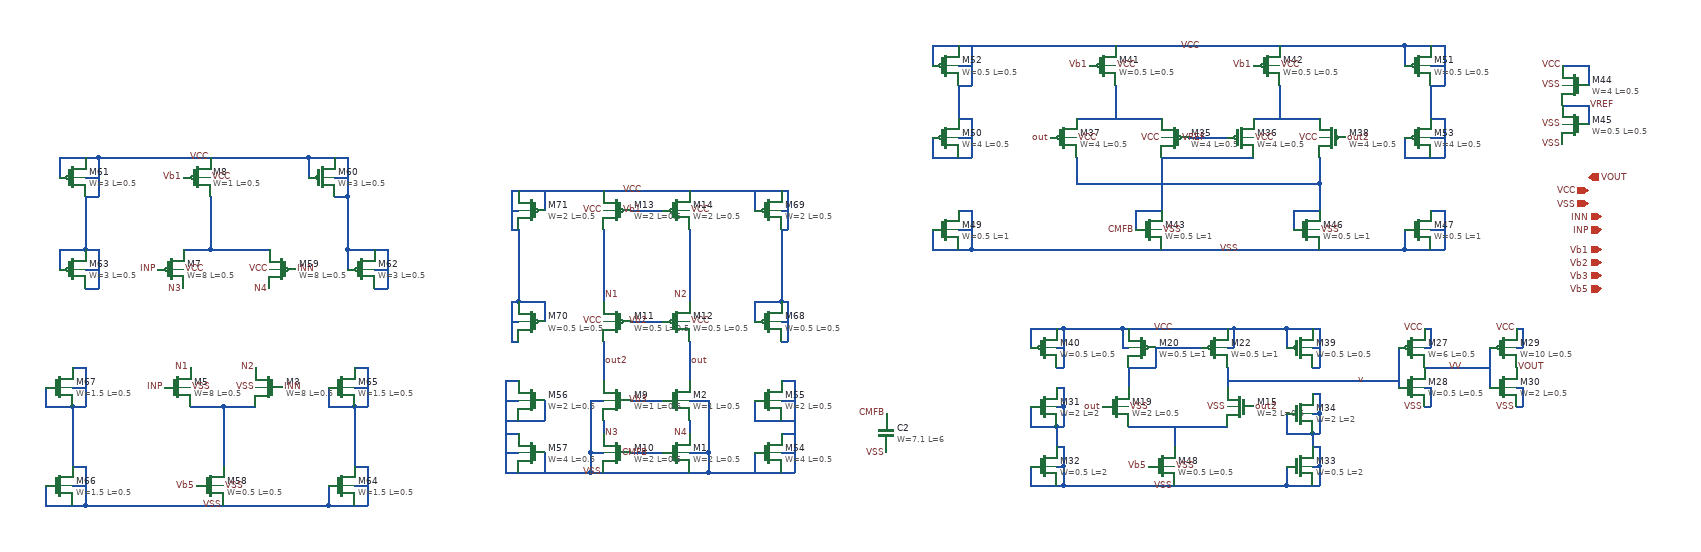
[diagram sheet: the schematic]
v {xschem version=3.4.0 file_version=1.2
}
G {}
K {}
V {}
S {}
E {}
N -1170 440 -1120 440 {
lab=#net1}
N -1190 200 -1100 200 {
lab=#net2}
N -1190 180 -1190 200 {
lab=#net2}
N -1220 440 -1170 440 {
lab=#net1}
N -1230 200 -1190 200 {
lab=#net2}
N -1170 440 -1170 470 {
lab=#net1}
N -1170 470 -1170 530 {
lab=#net1}
N -1190 120 -1190 180 {
lab=#net2}
N -1040 60 -1040 90 {
lab=VCC}
N -1040 60 -1000 60 {
lab=VCC}
N -1000 120 -990 120 {
lab=VCC}
N -990 120 -980 120 {
lab=VCC}
N -980 60 -980 120 {
lab=VCC}
N -1000 60 -980 60 {
lab=VCC}
N -1000 90 -980 90 {
lab=VCC}
N -1190 60 -1040 60 {
lab=VCC}
N -1420 60 -1420 90 {
lab=VCC}
N -1420 60 -1380 60 {
lab=VCC}
N -1380 120 -1370 120 {
lab=VCC}
N -1370 120 -1360 120 {
lab=VCC}
N -1360 60 -1360 120 {
lab=VCC}
N -1380 60 -1360 60 {
lab=VCC}
N -1380 90 -1360 90 {
lab=VCC}
N -1360 60 -1190 60 {
lab=VCC}
N -980 200 -980 230 {
lab=VCC}
N -980 200 -940 200 {
lab=VCC}
N -940 260 -930 260 {
lab=VCC}
N -930 260 -920 260 {
lab=VCC}
N -920 200 -920 260 {
lab=VCC}
N -940 200 -920 200 {
lab=VCC}
N -940 230 -920 230 {
lab=VCC}
N -980 120 -980 200 {
lab=VCC}
N -1420 200 -1420 230 {
lab=VCC}
N -1420 200 -1380 200 {
lab=VCC}
N -1380 260 -1370 260 {
lab=VCC}
N -1370 260 -1360 260 {
lab=VCC}
N -1360 200 -1360 260 {
lab=VCC}
N -1380 200 -1360 200 {
lab=VCC}
N -1380 230 -1360 230 {
lab=VCC}
N -1380 120 -1380 200 {
lab=VCC}
N -1010 590 -970 590 {
lab=VSS}
N -1010 560 -1010 590 {
lab=VSS}
N -970 530 -950 530 {
lab=VSS}
N -950 530 -950 590 {
lab=VSS}
N -970 590 -950 590 {
lab=VSS}
N -1170 590 -1010 590 {
lab=VSS}
N -970 560 -950 560 {
lab=VSS}
N -1010 440 -970 440 {
lab=VSS}
N -1010 410 -1010 440 {
lab=VSS}
N -970 380 -950 380 {
lab=VSS}
N -950 380 -950 440 {
lab=VSS}
N -970 440 -950 440 {
lab=VSS}
N -970 410 -950 410 {
lab=VSS}
N -970 440 -970 530 {
lab=VSS}
N -1440 590 -1400 590 {
lab=VSS}
N -1440 560 -1440 590 {
lab=VSS}
N -1400 530 -1380 530 {
lab=VSS}
N -1380 530 -1380 590 {
lab=VSS}
N -1400 590 -1380 590 {
lab=VSS}
N -1400 560 -1380 560 {
lab=VSS}
N -1440 440 -1400 440 {
lab=VSS}
N -1440 410 -1440 440 {
lab=VSS}
N -1400 380 -1380 380 {
lab=VSS}
N -1380 380 -1380 440 {
lab=VSS}
N -1400 440 -1380 440 {
lab=VSS}
N -1400 410 -1380 410 {
lab=VSS}
N -1400 440 -1400 530 {
lab=VSS}
N -1380 590 -1170 590 {
lab=VSS}
N -610 510 -590 510 {
lab=VSS}
N -610 510 -610 540 {
lab=VSS}
N -610 540 -430 540 {
lab=VSS}
N -430 510 -430 540 {
lab=VSS}
N -460 510 -430 510 {
lab=VSS}
N -460 460 -460 480 {
lab=N4}
N -590 460 -590 480 {
lab=N3}
N -550 430 -500 430 {
lab=Vb3}
N -610 430 -590 430 {
lab=VSS}
N -610 430 -610 510 {
lab=VSS}
N -460 430 -430 430 {
lab=VSS}
N -430 430 -430 510 {
lab=VSS}
N -550 310 -500 310 {
lab=Vb2}
N -550 140 -500 140 {
lab=Vb1}
N -590 110 -460 110 {
lab=VCC}
N -460 170 -460 280 {
lab=N2}
N -590 170 -590 280 {
lab=N1}
N -550 510 -530 510 {
lab=CMFB}
N -530 510 -500 510 {
lab=CMFB}
N -590 340 -590 400 {
lab=out2}
N -460 340 -460 400 {
lab=out}
N 910 -80 910 -50 {
lab=VCC}
N 870 -80 910 -80 {
lab=VCC}
N 910 -20 910 10 {
lab=AG2}
N 870 -20 910 -20 {
lab=AG2}
N 210 320 360 320 {
lab=VCC}
N 360 350 370 350 {
lab=VCC}
N 370 320 370 350 {
lab=VCC}
N 360 320 370 320 {
lab=VCC}
N 200 350 210 350 {
lab=VCC}
N 200 320 200 350 {
lab=VCC}
N 200 320 210 320 {
lab=VCC}
N 210 380 250 380 {
lab=#net3}
N 210 470 360 470 {
lab=#net4}
N 280 470 280 490 {
lab=#net4}
N 250 350 250 380 {
lab=#net3}
N 250 350 320 350 {
lab=#net3}
N 620 350 620 410 {
lab=v}
N 660 410 670 410 {
lab=VSS}
N 670 410 670 440 {
lab=VSS}
N 660 440 670 440 {
lab=VSS}
N 660 350 670 350 {
lab=VCC}
N 670 320 670 350 {
lab=VCC}
N 660 320 670 320 {
lab=VCC}
N 450 400 620 400 {
lab=v}
N 760 350 760 410 {
lab=VV}
N 800 410 810 410 {
lab=VSS}
N 810 410 810 440 {
lab=VSS}
N 800 440 810 440 {
lab=VSS}
N 800 350 810 350 {
lab=VCC}
N 810 320 810 350 {
lab=VCC}
N 800 320 810 320 {
lab=VCC}
N 660 380 760 380 {
lab=VV}
N 100 440 110 440 {
lab=VSS}
N 110 440 110 470 {
lab=VSS}
N 100 470 110 470 {
lab=VSS}
N 100 410 110 410 {
lab=VSS}
N 110 410 110 440 {
lab=VSS}
N 60 440 60 470 {
lab=VSS}
N 60 470 100 470 {
lab=VSS}
N 100 530 110 530 {
lab=VSS}
N 110 530 110 560 {
lab=VSS}
N 100 560 110 560 {
lab=VSS}
N 100 500 110 500 {
lab=VSS}
N 110 500 110 530 {
lab=VSS}
N 60 530 60 560 {
lab=VSS}
N 60 560 100 560 {
lab=VSS}
N 490 530 500 530 {
lab=VSS}
N 500 530 500 560 {
lab=VSS}
N 490 560 500 560 {
lab=VSS}
N 490 500 500 500 {
lab=VSS}
N 500 500 500 530 {
lab=VSS}
N 450 530 450 560 {
lab=VSS}
N 450 560 490 560 {
lab=VSS}
N 360 400 450 400 {
lab=v}
N 490 450 500 450 {
lab=VSS}
N 500 450 500 480 {
lab=VSS}
N 490 480 500 480 {
lab=VSS}
N 490 420 500 420 {
lab=VSS}
N 500 420 500 450 {
lab=VSS}
N 450 450 450 480 {
lab=VSS}
N 450 480 490 480 {
lab=VSS}
N 490 480 490 500 {
lab=VSS}
N 100 470 100 500 {
lab=VSS}
N 490 380 500 380 {
lab=VCC}
N 500 320 500 380 {
lab=VCC}
N 490 320 500 320 {
lab=VCC}
N 490 350 500 350 {
lab=VCC}
N 450 320 450 350 {
lab=VCC}
N 450 320 490 320 {
lab=VCC}
N 100 380 110 380 {
lab=VCC}
N 110 320 110 380 {
lab=VCC}
N 100 320 110 320 {
lab=VCC}
N 100 350 110 350 {
lab=VCC}
N 60 320 60 350 {
lab=VCC}
N 60 320 100 320 {
lab=VCC}
N 280 490 280 500 {
lab=#net4}
N 360 380 360 390 {
lab=v}
N 210 380 210 390 {
lab=#net3}
N 210 390 210 410 {
lab=#net3}
N 360 390 360 410 {
lab=v}
N 110 320 200 320 {
lab=VCC}
N 370 320 450 320 {
lab=VCC}
N 280 560 450 560 {
lab=VSS}
N 110 560 280 560 {
lab=VSS}
N 260 60 400 60 {
lab=CMFB}
N 130 60 130 100 {
lab=#net5}
N 130 100 500 100 {
lab=#net5}
N 500 60 500 100 {
lab=#net5}
N 130 0 260 0 {
lab=#net6}
N 400 0 500 0 {
lab=#net7}
N 440 -50 440 0 {
lab=#net7}
N 190 -50 190 0 {
lab=#net6}
N 300 30 360 30 {
lab=VREF}
N 500 100 500 140 {
lab=#net5}
N 460 140 460 170 {
lab=#net5}
N 460 140 500 140 {
lab=#net5}
N 220 140 220 170 {
lab=CMFB}
N 220 140 260 140 {
lab=CMFB}
N 260 60 260 140 {
lab=CMFB}
N 260 200 500 200 {
lab=VSS}
N 630 170 630 200 {
lab=VSS}
N 500 200 630 200 {
lab=VSS}
N 630 200 670 200 {
lab=VSS}
N 670 140 690 140 {
lab=VSS}
N 690 140 690 200 {
lab=VSS}
N 670 200 690 200 {
lab=VSS}
N 670 170 690 170 {
lab=VSS}
N 30 200 260 200 {
lab=VSS}
N -50 140 -30 140 {
lab=VSS}
N -30 140 -30 200 {
lab=VSS}
N -50 170 -30 170 {
lab=VSS}
N -90 170 -90 200 {
lab=VSS}
N -90 200 -50 200 {
lab=VSS}
N -90 30 -90 60 {
lab=VCC}
N -90 60 -50 60 {
lab=VCC}
N -50 0 -30 0 {
lab=VCC}
N -30 0 -30 60 {
lab=VCC}
N -50 60 -30 60 {
lab=VCC}
N -50 30 -30 30 {
lab=VCC}
N -50 200 -30 200 {
lab=VSS}
N -30 200 30 200 {
lab=VSS}
N 630 30 630 60 {
lab=VCC}
N 630 60 670 60 {
lab=VCC}
N 670 0 690 0 {
lab=VCC}
N 690 0 690 60 {
lab=VCC}
N 670 60 690 60 {
lab=VCC}
N 670 30 690 30 {
lab=VCC}
N 630 -110 630 -80 {
lab=VCC}
N 630 -110 670 -110 {
lab=VCC}
N 670 -110 690 -110 {
lab=VCC}
N 690 -110 690 -50 {
lab=VCC}
N 670 -50 690 -50 {
lab=VCC}
N 670 -80 690 -80 {
lab=VCC}
N 440 -110 630 -110 {
lab=VCC}
N -50 -110 190 -110 {
lab=VCC}
N -50 -50 -30 -50 {
lab=VCC}
N -30 -110 -30 -50 {
lab=VCC}
N -50 -80 -30 -80 {
lab=VCC}
N -90 -110 -90 -80 {
lab=VCC}
N -90 -110 -50 -110 {
lab=VCC}
N 190 -110 440 -110 {
lab=VCC}
N -430 540 -320 540 {
lab=VSS}
N -320 400 -300 400 {
lab=VSS}
N -300 400 -300 540 {
lab=VSS}
N -320 540 -300 540 {
lab=VSS}
N -320 510 -300 510 {
lab=VSS}
N -320 430 -300 430 {
lab=VSS}
N -320 460 -300 460 {
lab=VSS}
N -320 480 -300 480 {
lab=VSS}
N -360 510 -360 540 {
lab=VSS}
N -360 430 -360 460 {
lab=VSS}
N -360 460 -320 460 {
lab=VSS}
N -740 400 -720 400 {
lab=VSS}
N -740 400 -740 540 {
lab=VSS}
N -740 540 -720 540 {
lab=VSS}
N -720 540 -610 540 {
lab=VSS}
N -680 510 -680 540 {
lab=VSS}
N -740 480 -720 480 {
lab=VSS}
N -740 460 -720 460 {
lab=VSS}
N -740 430 -720 430 {
lab=VSS}
N -740 510 -720 510 {
lab=VSS}
N -680 430 -680 460 {
lab=VSS}
N -720 460 -680 460 {
lab=VSS}
N -460 110 -320 110 {
lab=VCC}
N -320 110 -310 110 {
lab=VCC}
N -310 110 -310 170 {
lab=VCC}
N -320 170 -310 170 {
lab=VCC}
N -320 280 -310 280 {
lab=VCC}
N -310 280 -310 340 {
lab=VCC}
N -320 340 -310 340 {
lab=VCC}
N -360 280 -360 310 {
lab=VCC}
N -360 280 -320 280 {
lab=VCC}
N -320 310 -310 310 {
lab=VCC}
N -320 170 -320 280 {
lab=VCC}
N -320 140 -310 140 {
lab=VCC}
N -360 110 -360 140 {
lab=VCC}
N -720 110 -590 110 {
lab=VCC}
N -680 110 -680 140 {
lab=VCC}
N -730 110 -720 110 {
lab=VCC}
N -730 110 -730 170 {
lab=VCC}
N -730 170 -720 170 {
lab=VCC}
N -720 170 -720 280 {
lab=VCC}
N -730 140 -720 140 {
lab=VCC}
N -730 280 -720 280 {
lab=VCC}
N -730 280 -730 340 {
lab=VCC}
N -730 340 -720 340 {
lab=VCC}
N -730 310 -720 310 {
lab=VCC}
N -680 280 -680 310 {
lab=VCC}
N -720 280 -680 280 {
lab=VCC}
N 670 -50 670 0 {
lab=VCC}
N -50 -50 -50 0 {
lab=VCC}
C {devices/iopin.sym} 910 110 0 0 {name=p83 lab=VCC}
C {devices/iopin.sym} 910 130 0 0 {name=p98 lab=VSS}
C {devices/ipin.sym} 930 150 0 0 {name=p105 lab=INN}
C {devices/ipin.sym} 930 170 0 0 {name=p106 lab=INP}
C {sky130_fd_pr/nfet_g5v0d10v5.sym} -1100 410 0 1 {name=M3
L=0.5
W=8
nf=1
mult=2
ad="'int((nf+1)/2) * W/nf * 0.29'" 
pd="'2*int((nf+1)/2) * (W/nf + 0.29)'"
as="'int((nf+2)/2) * W/nf * 0.29'" 
ps="'2*int((nf+2)/2) * (W/nf + 0.29)'"
nrd="'0.29 / W'" nrs="'0.29 / W'"
sa=0 sb=0 sd=0
model=nfet_g5v0d10v5
spiceprefix=X
}
C {sky130_fd_pr/nfet_g5v0d10v5.sym} -1240 410 0 0 {name=M5
L=0.5
W=8
nf=1
mult=2
ad="'int((nf+1)/2) * W/nf * 0.29'" 
pd="'2*int((nf+1)/2) * (W/nf + 0.29)'"
as="'int((nf+2)/2) * W/nf * 0.29'" 
ps="'2*int((nf+2)/2) * (W/nf + 0.29)'"
nrd="'0.29 / W'" nrs="'0.29 / W'"
sa=0 sb=0 sd=0
model=nfet_g5v0d10v5
spiceprefix=X
}
C {devices/lab_pin.sym} -1170 590 3 0 {name=p1 sig_type=std_logic lab=VSS}
C {devices/lab_pin.sym} -1220 380 1 0 {name=p10 sig_type=std_logic lab=N1}
C {devices/lab_pin.sym} -1120 380 1 0 {name=p11 sig_type=std_logic lab=N2}
C {devices/lab_pin.sym} -1080 410 2 0 {name=p16 sig_type=std_logic lab=INN}
C {devices/lab_pin.sym} -1260 410 2 1 {name=p28 sig_type=std_logic lab=INP}
C {devices/lab_pin.sym} -1230 90 0 0 {name=p30 sig_type=std_logic lab=Vb1}
C {devices/lab_pin.sym} -1190 60 1 0 {name=p31 sig_type=std_logic lab=VCC}
C {sky130_fd_pr/pfet_g5v0d10v5.sym} -1250 230 0 0 {name=M7
L=0.5
W=8
nf=1
mult=2
ad="'int((nf+1)/2) * W/nf * 0.29'" 
pd="'2*int((nf+1)/2) * (W/nf + 0.29)'"
as="'int((nf+2)/2) * W/nf * 0.29'" 
ps="'2*int((nf+2)/2) * (W/nf + 0.29)'"
nrd="'0.29 / W'" nrs="'0.29 / W'"
sa=0 sb=0 sd=0
model=pfet_g5v0d10v5
spiceprefix=X
}
C {devices/lab_pin.sym} -1100 260 3 0 {name=p36 sig_type=std_logic lab=N4}
C {devices/lab_pin.sym} -1230 260 3 0 {name=p37 sig_type=std_logic lab=N3}
C {devices/lab_pin.sym} -1060 230 2 0 {name=p40 sig_type=std_logic lab=INN}
C {devices/lab_pin.sym} -1270 230 2 1 {name=p44 sig_type=std_logic lab=INP}
C {devices/lab_pin.sym} -1120 410 0 0 {name=p45 sig_type=std_logic lab=VSS}
C {devices/lab_pin.sym} -1220 410 0 1 {name=p46 sig_type=std_logic lab=VSS}
C {sky130_fd_pr/pfet_g5v0d10v5.sym} -1210 90 0 0 {name=M8
L=0.5
W=1
nf=1
mult=4
ad="'int((nf+1)/2) * W/nf * 0.29'" 
pd="'2*int((nf+1)/2) * (W/nf + 0.29)'"
as="'int((nf+2)/2) * W/nf * 0.29'" 
ps="'2*int((nf+2)/2) * (W/nf + 0.29)'"
nrd="'0.29 / W'" nrs="'0.29 / W'"
sa=0 sb=0 sd=0
model=pfet_g5v0d10v5
spiceprefix=X
}
C {devices/lab_pin.sym} -1190 90 2 0 {name=p48 sig_type=std_logic lab=VCC}
C {sky130_fd_pr/nfet_g5v0d10v5.sym} -1190 560 0 0 {name=M58
L=0.5
W=0.5
nf=1
mult=4
ad="'int((nf+1)/2) * W/nf * 0.29'" 
pd="'2*int((nf+1)/2) * (W/nf + 0.29)'"
as="'int((nf+2)/2) * W/nf * 0.29'" 
ps="'2*int((nf+2)/2) * (W/nf + 0.29)'"
nrd="'0.29 / W'" nrs="'0.29 / W'"
sa=0 sb=0 sd=0
model=nfet_g5v0d10v5
spiceprefix=X
}
C {devices/lab_pin.sym} -1170 560 2 0 {name=p57 sig_type=std_logic lab=VSS}
C {devices/lab_pin.sym} -1210 560 0 0 {name=p58 sig_type=std_logic lab=Vb5}
C {devices/lab_pin.sym} -1230 230 0 1 {name=p63 sig_type=std_logic lab=VCC}
C {sky130_fd_pr/pfet_g5v0d10v5.sym} -1080 230 0 1 {name=M59
L=0.5
W=8
nf=1
mult=2
ad="'int((nf+1)/2) * W/nf * 0.29'" 
pd="'2*int((nf+1)/2) * (W/nf + 0.29)'"
as="'int((nf+2)/2) * W/nf * 0.29'" 
ps="'2*int((nf+2)/2) * (W/nf + 0.29)'"
nrd="'0.29 / W'" nrs="'0.29 / W'"
sa=0 sb=0 sd=0
model=pfet_g5v0d10v5
spiceprefix=X
}
C {devices/lab_pin.sym} -1100 230 0 0 {name=p64 sig_type=std_logic lab=VCC}
C {sky130_fd_pr/pfet_g5v0d10v5.sym} -1020 90 0 0 {name=M60
L=0.5
W=3
nf=1
mult=1
ad="'int((nf+1)/2) * W/nf * 0.29'" 
pd="'2*int((nf+1)/2) * (W/nf + 0.29)'"
as="'int((nf+2)/2) * W/nf * 0.29'" 
ps="'2*int((nf+2)/2) * (W/nf + 0.29)'"
nrd="'0.29 / W'" nrs="'0.29 / W'"
sa=0 sb=0 sd=0
model=pfet_g5v0d10v5
spiceprefix=X
}
C {sky130_fd_pr/pfet_g5v0d10v5.sym} -1400 90 0 0 {name=M61
L=0.5
W=3
nf=1
mult=1
ad="'int((nf+1)/2) * W/nf * 0.29'" 
pd="'2*int((nf+1)/2) * (W/nf + 0.29)'"
as="'int((nf+2)/2) * W/nf * 0.29'" 
ps="'2*int((nf+2)/2) * (W/nf + 0.29)'"
nrd="'0.29 / W'" nrs="'0.29 / W'"
sa=0 sb=0 sd=0
model=pfet_g5v0d10v5
spiceprefix=X
}
C {sky130_fd_pr/pfet_g5v0d10v5.sym} -960 230 0 0 {name=M62
L=0.5
W=3
nf=1
mult=1
ad="'int((nf+1)/2) * W/nf * 0.29'" 
pd="'2*int((nf+1)/2) * (W/nf + 0.29)'"
as="'int((nf+2)/2) * W/nf * 0.29'" 
ps="'2*int((nf+2)/2) * (W/nf + 0.29)'"
nrd="'0.29 / W'" nrs="'0.29 / W'"
sa=0 sb=0 sd=0
model=pfet_g5v0d10v5
spiceprefix=X
}
C {sky130_fd_pr/pfet_g5v0d10v5.sym} -1400 230 0 0 {name=M63
L=0.5
W=3
nf=1
mult=1
ad="'int((nf+1)/2) * W/nf * 0.29'" 
pd="'2*int((nf+1)/2) * (W/nf + 0.29)'"
as="'int((nf+2)/2) * W/nf * 0.29'" 
ps="'2*int((nf+2)/2) * (W/nf + 0.29)'"
nrd="'0.29 / W'" nrs="'0.29 / W'"
sa=0 sb=0 sd=0
model=pfet_g5v0d10v5
spiceprefix=X
}
C {sky130_fd_pr/nfet_g5v0d10v5.sym} -990 560 0 0 {name=M64
L=0.5
W=1.5
nf=1
mult=1
ad="'int((nf+1)/2) * W/nf * 0.29'" 
pd="'2*int((nf+1)/2) * (W/nf + 0.29)'"
as="'int((nf+2)/2) * W/nf * 0.29'" 
ps="'2*int((nf+2)/2) * (W/nf + 0.29)'"
nrd="'0.29 / W'" nrs="'0.29 / W'"
sa=0 sb=0 sd=0
model=nfet_g5v0d10v5
spiceprefix=X
}
C {sky130_fd_pr/nfet_g5v0d10v5.sym} -990 410 0 0 {name=M65
L=0.5
W=1.5
nf=1
mult=1
ad="'int((nf+1)/2) * W/nf * 0.29'" 
pd="'2*int((nf+1)/2) * (W/nf + 0.29)'"
as="'int((nf+2)/2) * W/nf * 0.29'" 
ps="'2*int((nf+2)/2) * (W/nf + 0.29)'"
nrd="'0.29 / W'" nrs="'0.29 / W'"
sa=0 sb=0 sd=0
model=nfet_g5v0d10v5
spiceprefix=X
}
C {sky130_fd_pr/nfet_g5v0d10v5.sym} -1420 560 0 0 {name=M66
L=0.5
W=1.5
nf=1
mult=1
ad="'int((nf+1)/2) * W/nf * 0.29'" 
pd="'2*int((nf+1)/2) * (W/nf + 0.29)'"
as="'int((nf+2)/2) * W/nf * 0.29'" 
ps="'2*int((nf+2)/2) * (W/nf + 0.29)'"
nrd="'0.29 / W'" nrs="'0.29 / W'"
sa=0 sb=0 sd=0
model=nfet_g5v0d10v5
spiceprefix=X
}
C {sky130_fd_pr/nfet_g5v0d10v5.sym} -1420 410 0 0 {name=M67
L=0.5
W=1.5
nf=1
mult=1
ad="'int((nf+1)/2) * W/nf * 0.29'" 
pd="'2*int((nf+1)/2) * (W/nf + 0.29)'"
as="'int((nf+2)/2) * W/nf * 0.29'" 
ps="'2*int((nf+2)/2) * (W/nf + 0.29)'"
nrd="'0.29 / W'" nrs="'0.29 / W'"
sa=0 sb=0 sd=0
model=nfet_g5v0d10v5
spiceprefix=X
}
C {devices/ipin.sym} 930 200 0 0 {name=p2 lab=Vb1}
C {devices/ipin.sym} 930 220 0 0 {name=p3 lab=Vb2}
C {devices/ipin.sym} 930 240 0 0 {name=p5 lab=Vb3}
C {devices/ipin.sym} 930 260 0 0 {name=p7 lab=Vb5}
C {sky130_fd_pr/nfet_g5v0d10v5.sym} -480 510 0 0 {name=M1
L=0.5
W=2
nf=1
mult=4
ad="'int((nf+1)/2) * W/nf * 0.29'" 
pd="'2*int((nf+1)/2) * (W/nf + 0.29)'"
as="'int((nf+2)/2) * W/nf * 0.29'" 
ps="'2*int((nf+2)/2) * (W/nf + 0.29)'"
nrd="'0.29 / W'" nrs="'0.29 / W'"
sa=0 sb=0 sd=0
model=nfet_g5v0d10v5
spiceprefix=X
}
C {sky130_fd_pr/nfet_g5v0d10v5.sym} -480 430 0 0 {name=M2
L=0.5
W=1
nf=1
mult=4
ad="'int((nf+1)/2) * W/nf * 0.29'" 
pd="'2*int((nf+1)/2) * (W/nf + 0.29)'"
as="'int((nf+2)/2) * W/nf * 0.29'" 
ps="'2*int((nf+2)/2) * (W/nf + 0.29)'"
nrd="'0.29 / W'" nrs="'0.29 / W'"
sa=0 sb=0 sd=0
model=nfet_g5v0d10v5
spiceprefix=X
}
C {devices/lab_pin.sym} -590 540 3 0 {name=p9 sig_type=std_logic lab=VSS}
C {devices/lab_pin.sym} -530 110 1 0 {name=p13 sig_type=std_logic lab=VCC}
C {devices/lab_pin.sym} -460 310 2 0 {name=p14 sig_type=std_logic lab=VCC}
C {sky130_fd_pr/nfet_g5v0d10v5.sym} -570 430 0 1 {name=M9
L=0.5
W=1
nf=1
mult=4
ad="'int((nf+1)/2) * W/nf * 0.29'" 
pd="'2*int((nf+1)/2) * (W/nf + 0.29)'"
as="'int((nf+2)/2) * W/nf * 0.29'" 
ps="'2*int((nf+2)/2) * (W/nf + 0.29)'"
nrd="'0.29 / W'" nrs="'0.29 / W'"
sa=0 sb=0 sd=0
model=nfet_g5v0d10v5
spiceprefix=X
}
C {sky130_fd_pr/nfet_g5v0d10v5.sym} -570 510 0 1 {name=M10
L=0.5
W=2
nf=1
mult=4
ad="'int((nf+1)/2) * W/nf * 0.29'" 
pd="'2*int((nf+1)/2) * (W/nf + 0.29)'"
as="'int((nf+2)/2) * W/nf * 0.29'" 
ps="'2*int((nf+2)/2) * (W/nf + 0.29)'"
nrd="'0.29 / W'" nrs="'0.29 / W'"
sa=0 sb=0 sd=0
model=nfet_g5v0d10v5
spiceprefix=X
}
C {sky130_fd_pr/pfet_g5v0d10v5.sym} -570 310 0 1 {name=M11
L=0.5
W=0.5
nf=1
mult=4
ad="'int((nf+1)/2) * W/nf * 0.29'" 
pd="'2*int((nf+1)/2) * (W/nf + 0.29)'"
as="'int((nf+2)/2) * W/nf * 0.29'" 
ps="'2*int((nf+2)/2) * (W/nf + 0.29)'"
nrd="'0.29 / W'" nrs="'0.29 / W'"
sa=0 sb=0 sd=0
model=pfet_g5v0d10v5
spiceprefix=X
}
C {sky130_fd_pr/pfet_g5v0d10v5.sym} -480 310 0 0 {name=M12
L=0.5
W=0.5
nf=1
mult=4
ad="'int((nf+1)/2) * W/nf * 0.29'" 
pd="'2*int((nf+1)/2) * (W/nf + 0.29)'"
as="'int((nf+2)/2) * W/nf * 0.29'" 
ps="'2*int((nf+2)/2) * (W/nf + 0.29)'"
nrd="'0.29 / W'" nrs="'0.29 / W'"
sa=0 sb=0 sd=0
model=pfet_g5v0d10v5
spiceprefix=X
}
C {devices/lab_pin.sym} -590 310 2 1 {name=p18 sig_type=std_logic lab=VCC}
C {devices/lab_pin.sym} -460 140 2 0 {name=p19 sig_type=std_logic lab=VCC}
C {sky130_fd_pr/pfet_g5v0d10v5.sym} -570 140 0 1 {name=M13
L=0.5
W=2
nf=1
mult=4
ad="'int((nf+1)/2) * W/nf * 0.29'" 
pd="'2*int((nf+1)/2) * (W/nf + 0.29)'"
as="'int((nf+2)/2) * W/nf * 0.29'" 
ps="'2*int((nf+2)/2) * (W/nf + 0.29)'"
nrd="'0.29 / W'" nrs="'0.29 / W'"
sa=0 sb=0 sd=0
model=pfet_g5v0d10v5
spiceprefix=X
}
C {sky130_fd_pr/pfet_g5v0d10v5.sym} -480 140 0 0 {name=M14
L=0.5
W=2
nf=1
mult=4
ad="'int((nf+1)/2) * W/nf * 0.29'" 
pd="'2*int((nf+1)/2) * (W/nf + 0.29)'"
as="'int((nf+2)/2) * W/nf * 0.29'" 
ps="'2*int((nf+2)/2) * (W/nf + 0.29)'"
nrd="'0.29 / W'" nrs="'0.29 / W'"
sa=0 sb=0 sd=0
model=pfet_g5v0d10v5
spiceprefix=X
}
C {devices/lab_pin.sym} -590 140 2 1 {name=p20 sig_type=std_logic lab=VCC}
C {devices/lab_pin.sym} -590 270 2 0 {name=p24 sig_type=std_logic lab=N1}
C {devices/lab_pin.sym} -460 270 0 0 {name=p25 sig_type=std_logic lab=N2}
C {devices/lab_pin.sym} -590 480 2 0 {name=p38 sig_type=std_logic lab=N3}
C {devices/lab_pin.sym} -460 480 0 0 {name=p39 sig_type=std_logic lab=N4}
C {devices/lab_pin.sym} -530 140 3 0 {name=p15 sig_type=std_logic lab=Vb1}
C {devices/lab_pin.sym} -520 310 1 0 {name=p55 sig_type=std_logic lab=Vb2}
C {devices/lab_pin.sym} -520 430 1 0 {name=p6 sig_type=std_logic lab=Vb3}
C {devices/lab_pin.sym} -590 370 2 0 {name=p67 sig_type=std_logic lab=out2}
C {devices/lab_pin.sym} 870 -80 1 0 {name=p100 sig_type=std_logic lab=VCC}
C {sky130_fd_pr/nfet_g5v0d10v5.sym} 890 -50 0 1 {name=M44
L=0.5
W=4
nf=1
mult=1
ad="'int((nf+1)/2) * W/nf * 0.29'" 
pd="'2*int((nf+1)/2) * (W/nf + 0.29)'"
as="'int((nf+2)/2) * W/nf * 0.29'" 
ps="'2*int((nf+2)/2) * (W/nf + 0.29)'"
nrd="'0.29 / W'" nrs="'0.29 / W'"
sa=0 sb=0 sd=0
model=nfet_g5v0d10v5
spiceprefix=X
}
C {devices/lab_pin.sym} 870 -50 2 1 {name=p101 sig_type=std_logic lab=VSS}
C {sky130_fd_pr/nfet_g5v0d10v5.sym} 890 10 0 1 {name=M45
L=0.5
W=0.5
nf=1
mult=1
ad="'int((nf+1)/2) * W/nf * 0.29'" 
pd="'2*int((nf+1)/2) * (W/nf + 0.29)'"
as="'int((nf+2)/2) * W/nf * 0.29'" 
ps="'2*int((nf+2)/2) * (W/nf + 0.29)'"
nrd="'0.29 / W'" nrs="'0.29 / W'"
sa=0 sb=0 sd=0
model=nfet_g5v0d10v5
spiceprefix=X
}
C {devices/lab_pin.sym} 870 10 2 1 {name=p102 sig_type=std_logic lab=VSS}
C {devices/lab_pin.sym} 870 40 3 0 {name=p103 sig_type=std_logic lab=VSS}
C {devices/lab_pin.sym} 910 -20 0 1 {name=p104 sig_type=std_logic lab=VREF}
C {devices/opin.sym} 910 90 0 0 {name=p47 lab=VOUT}
C {devices/lab_pin.sym} -460 370 0 1 {name=p75 sig_type=std_logic lab=out}
C {devices/lab_pin.sym} -160 450 3 1 {name=p69 sig_type=std_logic lab=CMFB}
C {devices/lab_pin.sym} -160 510 3 0 {name=p70 sig_type=std_logic lab=VSS}
C {sky130_fd_pr/pfet_g5v0d10v5.sym} 230 350 0 1 {name=M20
L=1
W=0.5
nf=1
mult=2
ad="'int((nf+1)/2) * W/nf * 0.29'" 
pd="'2*int((nf+1)/2) * (W/nf + 0.29)'"
as="'int((nf+2)/2) * W/nf * 0.29'" 
ps="'2*int((nf+2)/2) * (W/nf + 0.29)'"
nrd="'0.29 / W'" nrs="'0.29 / W'"
sa=0 sb=0 sd=0
model=pfet_g5v0d10v5
spiceprefix=X
}
C {sky130_fd_pr/pfet_g5v0d10v5.sym} 340 350 0 0 {name=M22
L=1
W=0.5
nf=1
mult=2
ad="'int((nf+1)/2) * W/nf * 0.29'" 
pd="'2*int((nf+1)/2) * (W/nf + 0.29)'"
as="'int((nf+2)/2) * W/nf * 0.29'" 
ps="'2*int((nf+2)/2) * (W/nf + 0.29)'"
nrd="'0.29 / W'" nrs="'0.29 / W'"
sa=0 sb=0 sd=0
model=pfet_g5v0d10v5
spiceprefix=X
}
C {devices/lab_pin.sym} 280 320 1 0 {name=p77 sig_type=std_logic lab=VCC}
C {sky130_fd_pr/nfet_g5v0d10v5.sym} 380 440 0 1 {name=M15
L=0.5
W=2
nf=1
mult=2
ad="'int((nf+1)/2) * W/nf * 0.29'" 
pd="'2*int((nf+1)/2) * (W/nf + 0.29)'"
as="'int((nf+2)/2) * W/nf * 0.29'" 
ps="'2*int((nf+2)/2) * (W/nf + 0.29)'"
nrd="'0.29 / W'" nrs="'0.29 / W'"
sa=0 sb=0 sd=0
model=nfet_g5v0d10v5
spiceprefix=X
}
C {sky130_fd_pr/nfet_g5v0d10v5.sym} 190 440 0 0 {name=M19
L=0.5
W=2
nf=1
mult=2
ad="'int((nf+1)/2) * W/nf * 0.29'" 
pd="'2*int((nf+1)/2) * (W/nf + 0.29)'"
as="'int((nf+2)/2) * W/nf * 0.29'" 
ps="'2*int((nf+2)/2) * (W/nf + 0.29)'"
nrd="'0.29 / W'" nrs="'0.29 / W'"
sa=0 sb=0 sd=0
model=nfet_g5v0d10v5
spiceprefix=X
}
C {devices/lab_pin.sym} 210 440 2 0 {name=p78 sig_type=std_logic lab=VSS}
C {devices/lab_pin.sym} 360 440 2 1 {name=p79 sig_type=std_logic lab=VSS}
C {devices/lab_pin.sym} 280 560 3 0 {name=p82 sig_type=std_logic lab=VSS}
C {devices/lab_pin.sym} 240 530 2 1 {name=p84 sig_type=std_logic lab=Vb5}
C {sky130_fd_pr/nfet_g5v0d10v5.sym} 260 530 0 0 {name=M48
L=0.5
W=0.5
nf=1
mult=4
ad="'int((nf+1)/2) * W/nf * 0.29'" 
pd="'2*int((nf+1)/2) * (W/nf + 0.29)'"
as="'int((nf+2)/2) * W/nf * 0.29'" 
ps="'2*int((nf+2)/2) * (W/nf + 0.29)'"
nrd="'0.29 / W'" nrs="'0.29 / W'"
sa=0 sb=0 sd=0
model=nfet_g5v0d10v5
spiceprefix=X
}
C {devices/lab_pin.sym} 280 530 2 0 {name=p85 sig_type=std_logic lab=VSS}
C {devices/lab_pin.sym} 170 440 0 0 {name=p80 sig_type=std_logic lab=out}
C {devices/lab_pin.sym} 400 440 2 0 {name=p81 sig_type=std_logic lab=out2}
C {devices/lab_pin.sym} -520 510 1 0 {name=p116 sig_type=std_logic lab=CMFB}
C {sky130_fd_pr/pfet_g5v0d10v5.sym} 640 350 0 0 {name=M27
L=0.5
W=6
nf=1
mult=1
ad="'int((nf+1)/2) * W/nf * 0.29'" 
pd="'2*int((nf+1)/2) * (W/nf + 0.29)'"
as="'int((nf+2)/2) * W/nf * 0.29'" 
ps="'2*int((nf+2)/2) * (W/nf + 0.29)'"
nrd="'0.29 / W'" nrs="'0.29 / W'"
sa=0 sb=0 sd=0
model=pfet_g5v0d10v5
spiceprefix=X
}
C {sky130_fd_pr/nfet_g5v0d10v5.sym} 640 410 0 0 {name=M28
L=0.5
W=0.5
nf=1
mult=1
ad="'int((nf+1)/2) * W/nf * 0.29'" 
pd="'2*int((nf+1)/2) * (W/nf + 0.29)'"
as="'int((nf+2)/2) * W/nf * 0.29'" 
ps="'2*int((nf+2)/2) * (W/nf + 0.29)'"
nrd="'0.29 / W'" nrs="'0.29 / W'"
sa=0 sb=0 sd=0
model=nfet_g5v0d10v5
spiceprefix=X
}
C {devices/lab_pin.sym} 660 320 1 0 {name=p86 sig_type=std_logic lab=VCC}
C {devices/lab_pin.sym} 660 440 3 0 {name=p87 sig_type=std_logic lab=VSS}
C {devices/lab_pin.sym} 570 400 3 0 {name=p88 sig_type=std_logic lab=v}
C {devices/lab_pin.sym} 800 380 2 0 {name=p89 sig_type=std_logic lab=VOUT}
C {sky130_fd_pr/pfet_g5v0d10v5.sym} 780 350 0 0 {name=M29
L=0.5
W=10
nf=1
mult=1
ad="'int((nf+1)/2) * W/nf * 0.29'" 
pd="'2*int((nf+1)/2) * (W/nf + 0.29)'"
as="'int((nf+2)/2) * W/nf * 0.29'" 
ps="'2*int((nf+2)/2) * (W/nf + 0.29)'"
nrd="'0.29 / W'" nrs="'0.29 / W'"
sa=0 sb=0 sd=0
model=pfet_g5v0d10v5
spiceprefix=X
}
C {sky130_fd_pr/nfet_g5v0d10v5.sym} 780 410 0 0 {name=M30
L=0.5
W=2
nf=1
mult=1
ad="'int((nf+1)/2) * W/nf * 0.29'" 
pd="'2*int((nf+1)/2) * (W/nf + 0.29)'"
as="'int((nf+2)/2) * W/nf * 0.29'" 
ps="'2*int((nf+2)/2) * (W/nf + 0.29)'"
nrd="'0.29 / W'" nrs="'0.29 / W'"
sa=0 sb=0 sd=0
model=nfet_g5v0d10v5
spiceprefix=X
}
C {devices/lab_pin.sym} 800 320 1 0 {name=p90 sig_type=std_logic lab=VCC}
C {devices/lab_pin.sym} 800 440 3 0 {name=p91 sig_type=std_logic lab=VSS}
C {sky130_fd_pr/nfet_g5v0d10v5.sym} 80 440 0 0 {name=M31
L=2
W=2
nf=1
mult=1
ad="'int((nf+1)/2) * W/nf * 0.29'" 
pd="'2*int((nf+1)/2) * (W/nf + 0.29)'"
as="'int((nf+2)/2) * W/nf * 0.29'" 
ps="'2*int((nf+2)/2) * (W/nf + 0.29)'"
nrd="'0.29 / W'" nrs="'0.29 / W'"
sa=0 sb=0 sd=0
model=nfet_g5v0d10v5
spiceprefix=X
}
C {sky130_fd_pr/nfet_g5v0d10v5.sym} 80 530 0 0 {name=M32
L=2
W=0.5
nf=1
mult=1
ad="'int((nf+1)/2) * W/nf * 0.29'" 
pd="'2*int((nf+1)/2) * (W/nf + 0.29)'"
as="'int((nf+2)/2) * W/nf * 0.29'" 
ps="'2*int((nf+2)/2) * (W/nf + 0.29)'"
nrd="'0.29 / W'" nrs="'0.29 / W'"
sa=0 sb=0 sd=0
model=nfet_g5v0d10v5
spiceprefix=X
}
C {sky130_fd_pr/nfet_g5v0d10v5.sym} 470 530 0 0 {name=M33
L=2
W=0.5
nf=1
mult=1
ad="'int((nf+1)/2) * W/nf * 0.29'" 
pd="'2*int((nf+1)/2) * (W/nf + 0.29)'"
as="'int((nf+2)/2) * W/nf * 0.29'" 
ps="'2*int((nf+2)/2) * (W/nf + 0.29)'"
nrd="'0.29 / W'" nrs="'0.29 / W'"
sa=0 sb=0 sd=0
model=nfet_g5v0d10v5
spiceprefix=X
}
C {sky130_fd_pr/nfet_g5v0d10v5.sym} 470 450 0 0 {name=M34
L=2
W=2
nf=1
mult=1
ad="'int((nf+1)/2) * W/nf * 0.29'" 
pd="'2*int((nf+1)/2) * (W/nf + 0.29)'"
as="'int((nf+2)/2) * W/nf * 0.29'" 
ps="'2*int((nf+2)/2) * (W/nf + 0.29)'"
nrd="'0.29 / W'" nrs="'0.29 / W'"
sa=0 sb=0 sd=0
model=nfet_g5v0d10v5
spiceprefix=X
}
C {sky130_fd_pr/pfet_g5v0d10v5.sym} 470 350 0 0 {name=M39
L=0.5
W=0.5
nf=1
mult=1
ad="'int((nf+1)/2) * W/nf * 0.29'" 
pd="'2*int((nf+1)/2) * (W/nf + 0.29)'"
as="'int((nf+2)/2) * W/nf * 0.29'" 
ps="'2*int((nf+2)/2) * (W/nf + 0.29)'"
nrd="'0.29 / W'" nrs="'0.29 / W'"
sa=0 sb=0 sd=0
model=pfet_g5v0d10v5
spiceprefix=X
}
C {sky130_fd_pr/pfet_g5v0d10v5.sym} 80 350 0 0 {name=M40
L=0.5
W=0.5
nf=1
mult=1
ad="'int((nf+1)/2) * W/nf * 0.29'" 
pd="'2*int((nf+1)/2) * (W/nf + 0.29)'"
as="'int((nf+2)/2) * W/nf * 0.29'" 
ps="'2*int((nf+2)/2) * (W/nf + 0.29)'"
nrd="'0.29 / W'" nrs="'0.29 / W'"
sa=0 sb=0 sd=0
model=pfet_g5v0d10v5
spiceprefix=X
}
C {sky130_fd_pr/pfet_g5v0d10v5.sym} 280 30 0 1 {name=M35
L=0.5
W=4
nf=1
mult=2
ad="'int((nf+1)/2) * W/nf * 0.29'" 
pd="'2*int((nf+1)/2) * (W/nf + 0.29)'"
as="'int((nf+2)/2) * W/nf * 0.29'" 
ps="'2*int((nf+2)/2) * (W/nf + 0.29)'"
nrd="'0.29 / W'" nrs="'0.29 / W'"
sa=0 sb=0 sd=0
model=pfet_g5v0d10v5
spiceprefix=X
}
C {sky130_fd_pr/pfet_g5v0d10v5.sym} 380 30 0 0 {name=M36
L=0.5
W=4
nf=1
mult=2
ad="'int((nf+1)/2) * W/nf * 0.29'" 
pd="'2*int((nf+1)/2) * (W/nf + 0.29)'"
as="'int((nf+2)/2) * W/nf * 0.29'" 
ps="'2*int((nf+2)/2) * (W/nf + 0.29)'"
nrd="'0.29 / W'" nrs="'0.29 / W'"
sa=0 sb=0 sd=0
model=pfet_g5v0d10v5
spiceprefix=X
}
C {sky130_fd_pr/pfet_g5v0d10v5.sym} 110 30 0 0 {name=M37
L=0.5
W=4
nf=1
mult=2
ad="'int((nf+1)/2) * W/nf * 0.29'" 
pd="'2*int((nf+1)/2) * (W/nf + 0.29)'"
as="'int((nf+2)/2) * W/nf * 0.29'" 
ps="'2*int((nf+2)/2) * (W/nf + 0.29)'"
nrd="'0.29 / W'" nrs="'0.29 / W'"
sa=0 sb=0 sd=0
model=pfet_g5v0d10v5
spiceprefix=X
}
C {sky130_fd_pr/pfet_g5v0d10v5.sym} 520 30 0 1 {name=M38
L=0.5
W=4
nf=1
mult=2
ad="'int((nf+1)/2) * W/nf * 0.29'" 
pd="'2*int((nf+1)/2) * (W/nf + 0.29)'"
as="'int((nf+2)/2) * W/nf * 0.29'" 
ps="'2*int((nf+2)/2) * (W/nf + 0.29)'"
nrd="'0.29 / W'" nrs="'0.29 / W'"
sa=0 sb=0 sd=0
model=pfet_g5v0d10v5
spiceprefix=X
}
C {devices/lab_pin.sym} 260 30 2 1 {name=p92 sig_type=std_logic lab=VCC}
C {devices/lab_pin.sym} 130 30 2 0 {name=p93 sig_type=std_logic lab=VCC}
C {devices/lab_pin.sym} 400 30 2 0 {name=p94 sig_type=std_logic lab=VCC}
C {devices/lab_pin.sym} 500 30 2 1 {name=p95 sig_type=std_logic lab=VCC}
C {sky130_fd_pr/pfet_g5v0d10v5.sym} 170 -80 0 0 {name=M41
L=0.5
W=0.5
nf=1
mult=2
ad="'int((nf+1)/2) * W/nf * 0.29'" 
pd="'2*int((nf+1)/2) * (W/nf + 0.29)'"
as="'int((nf+2)/2) * W/nf * 0.29'" 
ps="'2*int((nf+2)/2) * (W/nf + 0.29)'"
nrd="'0.29 / W'" nrs="'0.29 / W'"
sa=0 sb=0 sd=0
model=pfet_g5v0d10v5
spiceprefix=X
}
C {devices/lab_pin.sym} 190 -80 2 0 {name=p96 sig_type=std_logic lab=VCC}
C {devices/lab_pin.sym} 150 -80 0 0 {name=p97 sig_type=std_logic lab=Vb1}
C {devices/lab_pin.sym} 320 -110 1 0 {name=p99 sig_type=std_logic lab=VCC}
C {sky130_fd_pr/pfet_g5v0d10v5.sym} 420 -80 0 0 {name=M42
L=0.5
W=0.5
nf=1
mult=2
ad="'int((nf+1)/2) * W/nf * 0.29'" 
pd="'2*int((nf+1)/2) * (W/nf + 0.29)'"
as="'int((nf+2)/2) * W/nf * 0.29'" 
ps="'2*int((nf+2)/2) * (W/nf + 0.29)'"
nrd="'0.29 / W'" nrs="'0.29 / W'"
sa=0 sb=0 sd=0
model=pfet_g5v0d10v5
spiceprefix=X
}
C {devices/lab_pin.sym} 440 -80 2 0 {name=p107 sig_type=std_logic lab=VCC}
C {devices/lab_pin.sym} 400 -80 0 0 {name=p108 sig_type=std_logic lab=Vb1}
C {devices/lab_pin.sym} 330 30 3 1 {name=p109 sig_type=std_logic lab=VREF}
C {sky130_fd_pr/nfet_g5v0d10v5.sym} 240 170 0 0 {name=M43
L=1
W=0.5
nf=1
mult=2
ad="'int((nf+1)/2) * W/nf * 0.29'" 
pd="'2*int((nf+1)/2) * (W/nf + 0.29)'"
as="'int((nf+2)/2) * W/nf * 0.29'" 
ps="'2*int((nf+2)/2) * (W/nf + 0.29)'"
nrd="'0.29 / W'" nrs="'0.29 / W'"
sa=0 sb=0 sd=0
model=nfet_g5v0d10v5
spiceprefix=X
}
C {sky130_fd_pr/nfet_g5v0d10v5.sym} 480 170 0 0 {name=M46
L=1
W=0.5
nf=1
mult=2
ad="'int((nf+1)/2) * W/nf * 0.29'" 
pd="'2*int((nf+1)/2) * (W/nf + 0.29)'"
as="'int((nf+2)/2) * W/nf * 0.29'" 
ps="'2*int((nf+2)/2) * (W/nf + 0.29)'"
nrd="'0.29 / W'" nrs="'0.29 / W'"
sa=0 sb=0 sd=0
model=nfet_g5v0d10v5
spiceprefix=X
}
C {devices/lab_pin.sym} 260 170 2 0 {name=p110 sig_type=std_logic lab=VSS}
C {devices/lab_pin.sym} 500 170 2 0 {name=p111 sig_type=std_logic lab=VSS}
C {devices/lab_pin.sym} 380 200 3 0 {name=p112 sig_type=std_logic lab=VSS}
C {devices/lab_pin.sym} 220 170 0 0 {name=p113 sig_type=std_logic lab=CMFB}
C {devices/lab_pin.sym} 540 30 0 1 {name=p114 sig_type=std_logic lab=out2}
C {devices/lab_pin.sym} 90 30 0 0 {name=p115 sig_type=std_logic lab=out}
C {sky130_fd_pr/nfet_g5v0d10v5.sym} 650 170 0 0 {name=M47
L=1
W=0.5
nf=1
mult=1
ad="'int((nf+1)/2) * W/nf * 0.29'" 
pd="'2*int((nf+1)/2) * (W/nf + 0.29)'"
as="'int((nf+2)/2) * W/nf * 0.29'" 
ps="'2*int((nf+2)/2) * (W/nf + 0.29)'"
nrd="'0.29 / W'" nrs="'0.29 / W'"
sa=0 sb=0 sd=0
model=nfet_g5v0d10v5
spiceprefix=X
}
C {sky130_fd_pr/nfet_g5v0d10v5.sym} -70 170 0 0 {name=M49
L=1
W=0.5
nf=1
mult=1
ad="'int((nf+1)/2) * W/nf * 0.29'" 
pd="'2*int((nf+1)/2) * (W/nf + 0.29)'"
as="'int((nf+2)/2) * W/nf * 0.29'" 
ps="'2*int((nf+2)/2) * (W/nf + 0.29)'"
nrd="'0.29 / W'" nrs="'0.29 / W'"
sa=0 sb=0 sd=0
model=nfet_g5v0d10v5
spiceprefix=X
}
C {sky130_fd_pr/pfet_g5v0d10v5.sym} -70 30 0 0 {name=M50
L=0.5
W=4
nf=1
mult=1
ad="'int((nf+1)/2) * W/nf * 0.29'" 
pd="'2*int((nf+1)/2) * (W/nf + 0.29)'"
as="'int((nf+2)/2) * W/nf * 0.29'" 
ps="'2*int((nf+2)/2) * (W/nf + 0.29)'"
nrd="'0.29 / W'" nrs="'0.29 / W'"
sa=0 sb=0 sd=0
model=pfet_g5v0d10v5
spiceprefix=X
}
C {sky130_fd_pr/pfet_g5v0d10v5.sym} 650 -80 0 0 {name=M51
L=0.5
W=0.5
nf=1
mult=1
ad="'int((nf+1)/2) * W/nf * 0.29'" 
pd="'2*int((nf+1)/2) * (W/nf + 0.29)'"
as="'int((nf+2)/2) * W/nf * 0.29'" 
ps="'2*int((nf+2)/2) * (W/nf + 0.29)'"
nrd="'0.29 / W'" nrs="'0.29 / W'"
sa=0 sb=0 sd=0
model=pfet_g5v0d10v5
spiceprefix=X
}
C {sky130_fd_pr/pfet_g5v0d10v5.sym} -70 -80 0 0 {name=M52
L=0.5
W=0.5
nf=1
mult=1
ad="'int((nf+1)/2) * W/nf * 0.29'" 
pd="'2*int((nf+1)/2) * (W/nf + 0.29)'"
as="'int((nf+2)/2) * W/nf * 0.29'" 
ps="'2*int((nf+2)/2) * (W/nf + 0.29)'"
nrd="'0.29 / W'" nrs="'0.29 / W'"
sa=0 sb=0 sd=0
model=pfet_g5v0d10v5
spiceprefix=X
}
C {sky130_fd_pr/pfet_g5v0d10v5.sym} 650 30 0 0 {name=M53
L=0.5
W=4
nf=1
mult=1
ad="'int((nf+1)/2) * W/nf * 0.29'" 
pd="'2*int((nf+1)/2) * (W/nf + 0.29)'"
as="'int((nf+2)/2) * W/nf * 0.29'" 
ps="'2*int((nf+2)/2) * (W/nf + 0.29)'"
nrd="'0.29 / W'" nrs="'0.29 / W'"
sa=0 sb=0 sd=0
model=pfet_g5v0d10v5
spiceprefix=X
}
C {sky130_fd_pr/nfet_g5v0d10v5.sym} -340 510 0 0 {name=M54
L=0.5
W=4
nf=1
mult=1
ad="'int((nf+1)/2) * W/nf * 0.29'" 
pd="'2*int((nf+1)/2) * (W/nf + 0.29)'"
as="'int((nf+2)/2) * W/nf * 0.29'" 
ps="'2*int((nf+2)/2) * (W/nf + 0.29)'"
nrd="'0.29 / W'" nrs="'0.29 / W'"
sa=0 sb=0 sd=0
model=nfet_g5v0d10v5
spiceprefix=X
}
C {sky130_fd_pr/nfet_g5v0d10v5.sym} -340 430 0 0 {name=M55
L=0.5
W=2
nf=1
mult=1
ad="'int((nf+1)/2) * W/nf * 0.29'" 
pd="'2*int((nf+1)/2) * (W/nf + 0.29)'"
as="'int((nf+2)/2) * W/nf * 0.29'" 
ps="'2*int((nf+2)/2) * (W/nf + 0.29)'"
nrd="'0.29 / W'" nrs="'0.29 / W'"
sa=0 sb=0 sd=0
model=nfet_g5v0d10v5
spiceprefix=X
}
C {sky130_fd_pr/nfet_g5v0d10v5.sym} -700 430 0 1 {name=M56
L=0.5
W=2
nf=1
mult=1
ad="'int((nf+1)/2) * W/nf * 0.29'" 
pd="'2*int((nf+1)/2) * (W/nf + 0.29)'"
as="'int((nf+2)/2) * W/nf * 0.29'" 
ps="'2*int((nf+2)/2) * (W/nf + 0.29)'"
nrd="'0.29 / W'" nrs="'0.29 / W'"
sa=0 sb=0 sd=0
model=nfet_g5v0d10v5
spiceprefix=X
}
C {sky130_fd_pr/nfet_g5v0d10v5.sym} -700 510 0 1 {name=M57
L=0.5
W=4
nf=1
mult=1
ad="'int((nf+1)/2) * W/nf * 0.29'" 
pd="'2*int((nf+1)/2) * (W/nf + 0.29)'"
as="'int((nf+2)/2) * W/nf * 0.29'" 
ps="'2*int((nf+2)/2) * (W/nf + 0.29)'"
nrd="'0.29 / W'" nrs="'0.29 / W'"
sa=0 sb=0 sd=0
model=nfet_g5v0d10v5
spiceprefix=X
}
C {sky130_fd_pr/pfet_g5v0d10v5.sym} -340 310 0 0 {name=M68
L=0.5
W=0.5
nf=1
mult=1
ad="'int((nf+1)/2) * W/nf * 0.29'" 
pd="'2*int((nf+1)/2) * (W/nf + 0.29)'"
as="'int((nf+2)/2) * W/nf * 0.29'" 
ps="'2*int((nf+2)/2) * (W/nf + 0.29)'"
nrd="'0.29 / W'" nrs="'0.29 / W'"
sa=0 sb=0 sd=0
model=pfet_g5v0d10v5
spiceprefix=X
}
C {sky130_fd_pr/pfet_g5v0d10v5.sym} -340 140 0 0 {name=M69
L=0.5
W=2
nf=1
mult=1
ad="'int((nf+1)/2) * W/nf * 0.29'" 
pd="'2*int((nf+1)/2) * (W/nf + 0.29)'"
as="'int((nf+2)/2) * W/nf * 0.29'" 
ps="'2*int((nf+2)/2) * (W/nf + 0.29)'"
nrd="'0.29 / W'" nrs="'0.29 / W'"
sa=0 sb=0 sd=0
model=pfet_g5v0d10v5
spiceprefix=X
}
C {sky130_fd_pr/pfet_g5v0d10v5.sym} -700 310 0 1 {name=M70
L=0.5
W=0.5
nf=1
mult=1
ad="'int((nf+1)/2) * W/nf * 0.29'" 
pd="'2*int((nf+1)/2) * (W/nf + 0.29)'"
as="'int((nf+2)/2) * W/nf * 0.29'" 
ps="'2*int((nf+2)/2) * (W/nf + 0.29)'"
nrd="'0.29 / W'" nrs="'0.29 / W'"
sa=0 sb=0 sd=0
model=pfet_g5v0d10v5
spiceprefix=X
}
C {sky130_fd_pr/pfet_g5v0d10v5.sym} -700 140 0 1 {name=M71
L=0.5
W=2
nf=1
mult=1
ad="'int((nf+1)/2) * W/nf * 0.29'" 
pd="'2*int((nf+1)/2) * (W/nf + 0.29)'"
as="'int((nf+2)/2) * W/nf * 0.29'" 
ps="'2*int((nf+2)/2) * (W/nf + 0.29)'"
nrd="'0.29 / W'" nrs="'0.29 / W'"
sa=0 sb=0 sd=0
model=pfet_g5v0d10v5
spiceprefix=X
}
C {devices/lab_pin.sym} 720 380 3 0 {name=p117 sig_type=std_logic lab=VV}
C {sky130_fd_pr/cap_mim_m3_1.sym} -160 480 0 0 {name=C2 model=cap_mim_m3_1 W=7.1 L=6 MF=1 spiceprefix=X}
